# Hand-written LEF for the dla.db tests (no PDK data).
VERSION 5.8 ;
BUSBITCHARS "[]" ;
DIVIDERCHAR "/" ;
UNITS
  DATABASE MICRONS 2000 ;
END UNITS
MANUFACTURINGGRID 0.005 ;
PROPERTYDEFINITIONS
  LAYER foo STRING ;
END PROPERTYDEFINITIONS

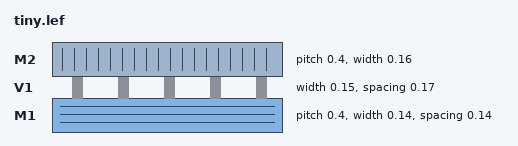
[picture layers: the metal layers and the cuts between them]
LAYER M1
  TYPE ROUTING ;
  DIRECTION HORIZONTAL ;
  PITCH 0.4 ;
  WIDTH 0.14 ;
  SPACING 0.14 ;
  AREA 0.06 ;
  RESISTANCE RPERSQ 0.1 ;
  CAPACITANCE CPERSQDIST 3e-05 ;
  EDGECAPACITANCE 2.5e-05 ;
  PROPERTY foo "a ; b" ;
END M1
LAYER V1
  TYPE CUT ;
  WIDTH 0.15 ;
  SPACING 0.17 ;
  ENCLOSURE BELOW 0.0 0.05 ;
  ENCLOSURE ABOVE 0.01 0.04 ;
  RESISTANCE 4.5 ;
END V1
LAYER M2
  TYPE ROUTING ;
  DIRECTION VERTICAL ;
  PITCH 0.4 0.5 ;
  OFFSET 0.2 ;
  WIDTH 0.16 ;
  SPACINGTABLE
    PARALLELRUNLENGTH 0.0 1.0
    WIDTH 0.0  0.16 0.16
    WIDTH 0.5  0.16 0.30 ;
END M2

VIA V1_0 DEFAULT
  RESISTANCE 4.5 ;
  LAYER M1 ;
    RECT -0.125 -0.075 0.125 0.075 ;
  LAYER V1 ;
    RECT -0.075 -0.075 0.075 0.075 ;
  LAYER M2 ;
    RECT -0.085 -0.115 0.085 0.115 ;
END V1_0

VIARULE V1_GEN GENERATE
  LAYER M1 ;
    ENCLOSURE 0.05 0.0 ;
  LAYER M2 ;
    ENCLOSURE 0.04 0.01 ;
  LAYER V1 ;
    RECT -0.075 -0.075 0.075 0.075 ;
    SPACING 0.32 BY 0.32 ;
END V1_GEN

SITE core
  CLASS CORE ;
  SYMMETRY Y ;
  SIZE 0.4 BY 2.8 ;
END core

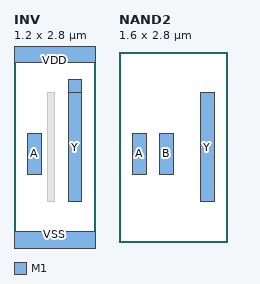
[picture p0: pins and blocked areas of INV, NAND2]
MACRO INV
  CLASS CORE ;
  ORIGIN 0 0 ;
  FOREIGN INV 0 0 ;
  SIZE 1.2 BY 2.8 ;
  SYMMETRY X Y ;
  SITE core ;
  PIN A
    DIRECTION INPUT ;
    USE SIGNAL ;
    ANTENNAGATEAREA 0.1 LAYER M1 ;
    PORT
      LAYER M1 ;
        RECT 0.2 1.0 0.4 1.6 ;
    END
  END A
  PIN Y
    DIRECTION OUTPUT ;
    USE SIGNAL ;
    PORT
      LAYER M1 ;
        RECT 0.8 0.6 1.0 2.2 ;
        POLYGON 0.8 2.2 1.0 2.2 1.0 2.4 0.8 2.4 ;
    END
  END Y
  PIN VDD
    DIRECTION INOUT ;
    USE POWER ;
    SHAPE ABUTMENT ;
    PORT
      LAYER M1 ;
        RECT 0 2.65 1.2 2.95 ;
    END
  END VDD
  PIN VSS
    DIRECTION INOUT ;
    USE GROUND ;
    SHAPE ABUTMENT ;
    PORT
      LAYER M1 ;
        RECT 0 -0.15 1.2 0.15 ;
    END
  END VSS
  OBS
    LAYER M1 ;
      RECT 0.5 0.6 0.6 2.2 ;
  END
END INV

MACRO NAND2
  CLASS CORE ;
  ORIGIN 0.1 0 ;
  SIZE 1.6 BY 2.8 ;
  SITE core ;
  PIN A
    DIRECTION INPUT ;
    PORT
      LAYER M1 ;
        RECT 0.1 1.0 0.3 1.6 ;
    END
  END A
  PIN B
    DIRECTION INPUT ;
    PORT
      LAYER M1 ;
        RECT 0.5 1.0 0.7 1.6 ;
    END
  END B
  PIN Y
    DIRECTION OUTPUT ;
    PORT
      LAYER M1 ;
        RECT 1.1 0.6 1.3 2.2 ;
    END
  END Y
END NAND2

END LIBRARY
